One B-rep face of a CAD part: STEP entity #76278.
In plain terms, the planar face has unit normal (0, 0, 1).
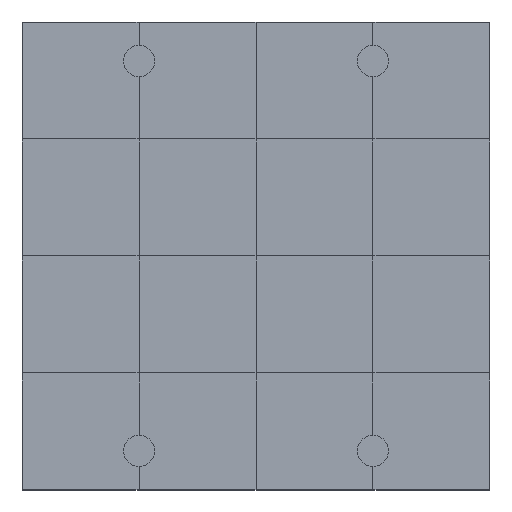
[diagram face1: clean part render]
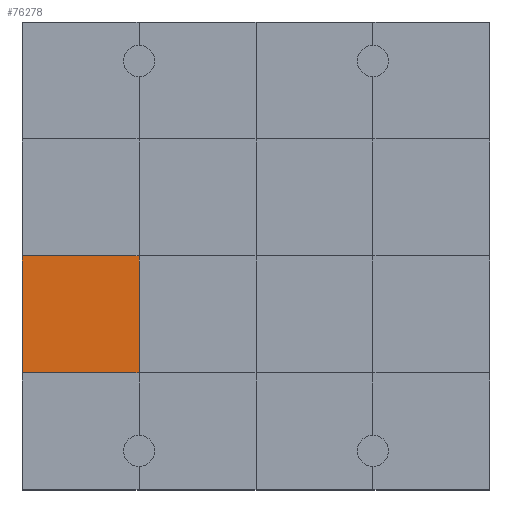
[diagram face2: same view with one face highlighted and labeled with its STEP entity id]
Its self-contained STEP definition (entity closure, numbers rounded to 3 decimals):
#75828 = VERTEX_POINT('',#75829);
#75829 = CARTESIAN_POINT('',(0.,3.,1.2));
#75843 = PLANE('',#75844);
#75844 = AXIS2_PLACEMENT_3D('',#75845,#75846,#75847);
#75845 = CARTESIAN_POINT('',(0.,3.,0.));
#75846 = DIRECTION('',(1.,0.,-0.));
#75847 = DIRECTION('',(0.,0.,1.));
#75869 = PLANE('',#75870);
#75870 = AXIS2_PLACEMENT_3D('',#75871,#75872,#75873);
#75871 = CARTESIAN_POINT('',(0.,0.,1.2));
#75872 = DIRECTION('',(0.,0.,1.));
#75873 = DIRECTION('',(1.,0.,-0.));
#76020 = VERTEX_POINT('',#76021);
#76021 = CARTESIAN_POINT('',(3.,3.,1.2));
#76042 = EDGE_CURVE('',#75828,#76020,#76043,.T.);
#76043 = SURFACE_CURVE('',#76044,(#76048,#76055),.PCURVE_S1.);
#76044 = LINE('',#76045,#76046);
#76045 = CARTESIAN_POINT('',(0.,3.,1.2));
#76046 = VECTOR('',#76047,1.);
#76047 = DIRECTION('',(1.,0.,-0.));
#76048 = PCURVE('',#75869,#76049);
#76049 = DEFINITIONAL_REPRESENTATION('',(#76050),#76054);
#76050 = LINE('',#76051,#76052);
#76051 = CARTESIAN_POINT('',(0.,3.));
#76052 = VECTOR('',#76053,1.);
#76053 = DIRECTION('',(1.,0.));
#76054 = ( GEOMETRIC_REPRESENTATION_CONTEXT(2) 
PARAMETRIC_REPRESENTATION_CONTEXT() REPRESENTATION_CONTEXT('2D SPACE',''
  ) );
#76055 = PCURVE('',#76056,#76061);
#76056 = PLANE('',#76057);
#76057 = AXIS2_PLACEMENT_3D('',#76058,#76059,#76060);
#76058 = CARTESIAN_POINT('',(0.,3.,1.2));
#76059 = DIRECTION('',(0.,0.,1.));
#76060 = DIRECTION('',(1.,0.,-0.));
#76061 = DEFINITIONAL_REPRESENTATION('',(#76062),#76066);
#76062 = LINE('',#76063,#76064);
#76063 = CARTESIAN_POINT('',(0.,0.));
#76064 = VECTOR('',#76065,1.);
#76065 = DIRECTION('',(1.,0.));
#76066 = ( GEOMETRIC_REPRESENTATION_CONTEXT(2) 
PARAMETRIC_REPRESENTATION_CONTEXT() REPRESENTATION_CONTEXT('2D SPACE',''
  ) );
#76101 = VERTEX_POINT('',#76102);
#76102 = CARTESIAN_POINT('',(0.,6.,1.2));
#76128 = EDGE_CURVE('',#75828,#76101,#76129,.T.);
#76129 = SURFACE_CURVE('',#76130,(#76134,#76141),.PCURVE_S1.);
#76130 = LINE('',#76131,#76132);
#76131 = CARTESIAN_POINT('',(0.,3.,1.2));
#76132 = VECTOR('',#76133,1.);
#76133 = DIRECTION('',(-0.,1.,0.));
#76134 = PCURVE('',#75843,#76135);
#76135 = DEFINITIONAL_REPRESENTATION('',(#76136),#76140);
#76136 = LINE('',#76137,#76138);
#76137 = CARTESIAN_POINT('',(1.2,0.));
#76138 = VECTOR('',#76139,1.);
#76139 = DIRECTION('',(0.,-1.));
#76140 = ( GEOMETRIC_REPRESENTATION_CONTEXT(2) 
PARAMETRIC_REPRESENTATION_CONTEXT() REPRESENTATION_CONTEXT('2D SPACE',''
  ) );
#76141 = PCURVE('',#76056,#76142);
#76142 = DEFINITIONAL_REPRESENTATION('',(#76143),#76147);
#76143 = LINE('',#76144,#76145);
#76144 = CARTESIAN_POINT('',(0.,0.));
#76145 = VECTOR('',#76146,1.);
#76146 = DIRECTION('',(0.,1.));
#76147 = ( GEOMETRIC_REPRESENTATION_CONTEXT(2) 
PARAMETRIC_REPRESENTATION_CONTEXT() REPRESENTATION_CONTEXT('2D SPACE',''
  ) );
#76278 = ADVANCED_FACE('',(#76279),#76056,.T.);
#76279 = FACE_BOUND('',#76280,.T.);
#76280 = EDGE_LOOP('',(#76281,#76282,#76283,#76311));
#76281 = ORIENTED_EDGE('',*,*,#76128,.F.);
#76282 = ORIENTED_EDGE('',*,*,#76042,.T.);
#76283 = ORIENTED_EDGE('',*,*,#76284,.T.);
#76284 = EDGE_CURVE('',#76020,#76285,#76287,.T.);
#76285 = VERTEX_POINT('',#76286);
#76286 = CARTESIAN_POINT('',(3.,6.,1.2));
#76287 = SURFACE_CURVE('',#76288,(#76292,#76299),.PCURVE_S1.);
#76288 = LINE('',#76289,#76290);
#76289 = CARTESIAN_POINT('',(3.,3.,1.2));
#76290 = VECTOR('',#76291,1.);
#76291 = DIRECTION('',(-0.,1.,0.));
#76292 = PCURVE('',#76056,#76293);
#76293 = DEFINITIONAL_REPRESENTATION('',(#76294),#76298);
#76294 = LINE('',#76295,#76296);
#76295 = CARTESIAN_POINT('',(3.,0.));
#76296 = VECTOR('',#76297,1.);
#76297 = DIRECTION('',(0.,1.));
#76298 = ( GEOMETRIC_REPRESENTATION_CONTEXT(2) 
PARAMETRIC_REPRESENTATION_CONTEXT() REPRESENTATION_CONTEXT('2D SPACE',''
  ) );
#76299 = PCURVE('',#76300,#76305);
#76300 = PLANE('',#76301);
#76301 = AXIS2_PLACEMENT_3D('',#76302,#76303,#76304);
#76302 = CARTESIAN_POINT('',(3.,3.,1.2));
#76303 = DIRECTION('',(0.,0.,1.));
#76304 = DIRECTION('',(1.,0.,-0.));
#76305 = DEFINITIONAL_REPRESENTATION('',(#76306),#76310);
#76306 = LINE('',#76307,#76308);
#76307 = CARTESIAN_POINT('',(0.,0.));
#76308 = VECTOR('',#76309,1.);
#76309 = DIRECTION('',(0.,1.));
#76310 = ( GEOMETRIC_REPRESENTATION_CONTEXT(2) 
PARAMETRIC_REPRESENTATION_CONTEXT() REPRESENTATION_CONTEXT('2D SPACE',''
  ) );
#76311 = ORIENTED_EDGE('',*,*,#76312,.F.);
#76312 = EDGE_CURVE('',#76101,#76285,#76313,.T.);
#76313 = SURFACE_CURVE('',#76314,(#76318,#76325),.PCURVE_S1.);
#76314 = LINE('',#76315,#76316);
#76315 = CARTESIAN_POINT('',(0.,6.,1.2));
#76316 = VECTOR('',#76317,1.);
#76317 = DIRECTION('',(1.,0.,-0.));
#76318 = PCURVE('',#76056,#76319);
#76319 = DEFINITIONAL_REPRESENTATION('',(#76320),#76324);
#76320 = LINE('',#76321,#76322);
#76321 = CARTESIAN_POINT('',(0.,3.));
#76322 = VECTOR('',#76323,1.);
#76323 = DIRECTION('',(1.,0.));
#76324 = ( GEOMETRIC_REPRESENTATION_CONTEXT(2) 
PARAMETRIC_REPRESENTATION_CONTEXT() REPRESENTATION_CONTEXT('2D SPACE',''
  ) );
#76325 = PCURVE('',#76326,#76331);
#76326 = PLANE('',#76327);
#76327 = AXIS2_PLACEMENT_3D('',#76328,#76329,#76330);
#76328 = CARTESIAN_POINT('',(0.,6.,1.2));
#76329 = DIRECTION('',(0.,0.,1.));
#76330 = DIRECTION('',(1.,0.,-0.));
#76331 = DEFINITIONAL_REPRESENTATION('',(#76332),#76336);
#76332 = LINE('',#76333,#76334);
#76333 = CARTESIAN_POINT('',(0.,0.));
#76334 = VECTOR('',#76335,1.);
#76335 = DIRECTION('',(1.,0.));
#76336 = ( GEOMETRIC_REPRESENTATION_CONTEXT(2) 
PARAMETRIC_REPRESENTATION_CONTEXT() REPRESENTATION_CONTEXT('2D SPACE',''
  ) );
